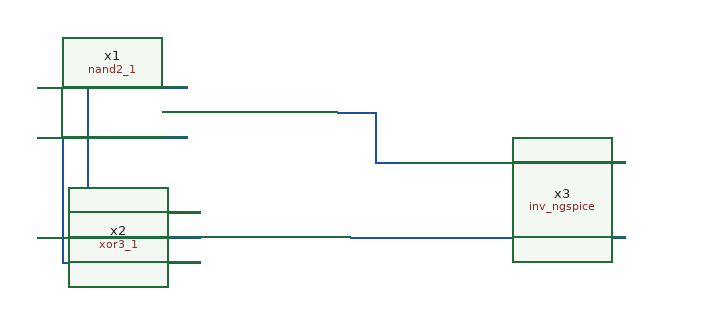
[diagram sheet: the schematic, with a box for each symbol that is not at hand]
v {xschem version=3.4.5 file_version=1.2
}
G {}
K {}
V {}
S {}
E {}
N 940 -610 970 -610 {}
N 970 -610 970 -570 {}
N 970 -570 990 -570 {}
N 950 -510 1170 -510 {}
N 1070 -570 1170 -570 {}
N 700 -630 820 -630 {}
N 700 -590 820 -590 {}
N 740 -530 830 -530 {}
N 740 -630 740 -530 {}
N 700 -510 830 -510 {}
N 720 -590 720 -490 {}
N 720 -490 830 -490 {}
C {nand2_1.sym} 880 -610 0 0 {name=x1 VGND=VGND VNB=VNB VPB=VPB VPWR=VPWR prefix=sky130_fd_sc_hd__ }
C {xor3_1.sym} 890 -510 0 0 {name=x2 VGND=VGND VNB=VNB VPB=VPB VPWR=VPWR prefix=sky130_fd_sc_hd__ }
C {inv_ngspice.sym} 1030 -570 0 0 {name=x3 RUP=2000 RDOWN=1000}
